VERSION 5.8 ;
BUSBITCHARS "[]" ;
DIVIDERCHAR "/" ;

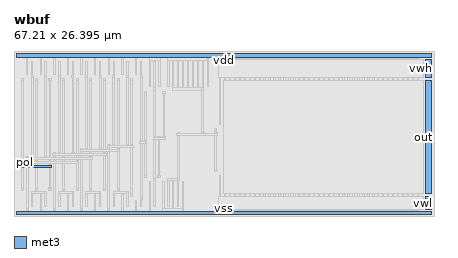
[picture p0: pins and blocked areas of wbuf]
MACRO wbuf
  CLASS BLOCK ;
  FOREIGN wbuf 0 0 ;
  ORIGIN 0 0 ;
  SIZE 67.210 BY 26.395 ;
  SYMMETRY X Y ;
  PIN out
    DIRECTION OUTPUT ;
    USE SIGNAL ;
    PORT
      LAYER met3 ;
        RECT 65.810 3.535 66.750 21.685 ;
    END
  END out
  PIN pol
    DIRECTION INPUT ;
    USE SIGNAL ;
    PORT
      LAYER met3 ;
        RECT 0.460 8.455 1.400 8.795 ;
    END
  END pol
  PIN vdd
    DIRECTION INOUT ;
    USE POWER ;
    PORT
      LAYER met3 ;
        RECT 0.460 25.435 66.750 25.935 ;
    END
  END vdd
  PIN vss
    DIRECTION INOUT ;
    USE GROUND ;
    PORT
      LAYER met3 ;
        RECT 0.460 0.185 66.750 0.685 ;
    END
  END vss
  PIN vwh
    DIRECTION INOUT ;
    USE SIGNAL ;
    PORT
      LAYER met3 ;
        RECT 65.810 22.135 66.750 24.985 ;
    END
  END vwh
  PIN vwl
    DIRECTION INOUT ;
    USE SIGNAL ;
    PORT
      LAYER met3 ;
        RECT 65.810 0.985 66.750 3.085 ;
    END
  END vwl
  PIN wp
    DIRECTION INPUT ;
    USE SIGNAL ;
    PORT
      LAYER met3 ;
        RECT 0.460 7.815 6.020 8.155 ;
    END
  END wp
  OBS
    LAYER li1 ;
      RECT 0.000 0.000 67.210 26.395 ;
    LAYER met1 ;
      RECT 20.220 2.960 20.450 2.965 ;
      RECT 20.170 2.630 20.500 2.960 ;
      RECT 20.220 1.455 20.450 2.630 ;
      RECT 1.940 0.930 1.990 1.260 ;
      RECT 2.220 0.930 2.270 1.260 ;
      RECT 1.990 0.925 2.220 3.455 ;
      RECT 6.300 0.930 6.350 1.260 ;
      RECT 6.580 0.930 6.630 1.260 ;
      RECT 6.350 0.925 6.580 3.455 ;
      RECT 10.660 0.930 10.710 1.260 ;
      RECT 10.940 0.930 10.990 1.260 ;
      RECT 10.710 0.925 10.940 3.455 ;
      RECT 15.020 0.930 15.070 1.260 ;
      RECT 15.300 0.930 15.350 1.260 ;
      RECT 15.070 0.925 15.300 3.455 ;
      RECT 18.680 3.145 19.020 3.485 ;
      RECT 2.780 1.455 3.010 3.625 ;
      RECT 2.780 3.625 4.960 3.965 ;
      RECT 4.960 1.455 5.190 3.965 ;
      RECT 7.140 1.455 7.370 3.625 ;
      RECT 7.140 3.625 9.320 3.965 ;
      RECT 9.320 1.455 9.550 3.965 ;
      RECT 11.500 1.455 11.730 3.625 ;
      RECT 11.500 3.625 13.680 3.965 ;
      RECT 13.680 1.455 13.910 3.965 ;
      RECT 15.860 1.455 16.090 3.625 ;
      RECT 15.860 3.625 18.040 3.965 ;
      RECT 18.040 1.455 18.270 3.965 ;
      RECT 1.240 4.145 1.580 4.485 ;
      RECT 3.420 4.145 3.760 4.485 ;
      RECT 5.600 4.145 5.940 4.485 ;
      RECT 7.780 4.145 8.120 4.485 ;
      RECT 9.960 4.145 10.300 4.485 ;
      RECT 12.140 4.145 12.480 4.485 ;
      RECT 14.320 4.145 14.660 4.485 ;
      RECT 16.500 4.145 16.840 4.485 ;
      RECT 19.430 0.685 19.660 2.455 ;
      RECT 4.170 0.685 4.400 3.455 ;
      RECT 8.530 0.685 8.760 3.455 ;
      RECT 12.890 0.685 13.120 3.455 ;
      RECT 17.250 0.685 17.480 3.455 ;
      RECT 21.610 0.685 21.840 5.455 ;
      RECT 23.790 1.265 24.020 5.455 ;
      RECT 25.370 1.265 25.600 5.455 ;
      RECT 27.180 0.185 66.750 0.685 ;
      RECT 26.950 0.185 27.180 5.455 ;
      RECT 23.790 0.185 26.950 1.265 ;
      RECT 0.460 0.185 23.790 0.685 ;
      RECT 22.400 5.960 22.630 5.965 ;
      RECT 22.350 5.630 22.680 5.960 ;
      RECT 22.400 1.455 22.630 5.630 ;
      RECT 24.580 1.455 24.810 5.625 ;
      RECT 26.390 5.630 26.440 5.960 ;
      RECT 24.580 5.625 26.390 5.965 ;
      RECT 26.160 1.455 26.390 5.625 ;
      RECT 32.890 2.750 33.120 6.455 ;
      RECT 32.840 2.420 33.170 2.750 ;
      RECT 32.890 1.950 33.120 2.420 ;
      RECT 32.840 1.620 33.170 1.950 ;
      RECT 32.890 1.265 33.120 1.620 ;
      RECT 34.470 2.750 34.700 6.455 ;
      RECT 34.420 2.420 34.750 2.750 ;
      RECT 34.470 1.950 34.700 2.420 ;
      RECT 34.420 1.620 34.750 1.950 ;
      RECT 34.470 1.265 34.700 1.620 ;
      RECT 36.050 2.750 36.280 6.455 ;
      RECT 36.000 2.420 36.330 2.750 ;
      RECT 36.050 1.950 36.280 2.420 ;
      RECT 36.000 1.620 36.330 1.950 ;
      RECT 36.050 1.265 36.280 1.620 ;
      RECT 37.630 2.750 37.860 6.455 ;
      RECT 37.580 2.420 37.910 2.750 ;
      RECT 37.630 1.950 37.860 2.420 ;
      RECT 37.580 1.620 37.910 1.950 ;
      RECT 37.630 1.265 37.860 1.620 ;
      RECT 39.210 2.750 39.440 6.455 ;
      RECT 39.160 2.420 39.490 2.750 ;
      RECT 39.210 1.950 39.440 2.420 ;
      RECT 39.160 1.620 39.490 1.950 ;
      RECT 39.210 1.265 39.440 1.620 ;
      RECT 40.790 2.750 41.020 6.455 ;
      RECT 40.740 2.420 41.070 2.750 ;
      RECT 40.790 1.950 41.020 2.420 ;
      RECT 40.740 1.620 41.070 1.950 ;
      RECT 40.790 1.265 41.020 1.620 ;
      RECT 42.370 2.750 42.600 6.455 ;
      RECT 42.320 2.420 42.650 2.750 ;
      RECT 42.370 1.950 42.600 2.420 ;
      RECT 42.320 1.620 42.650 1.950 ;
      RECT 42.370 1.265 42.600 1.620 ;
      RECT 43.950 2.750 44.180 6.455 ;
      RECT 43.900 2.420 44.230 2.750 ;
      RECT 43.950 1.950 44.180 2.420 ;
      RECT 43.900 1.620 44.230 1.950 ;
      RECT 43.950 1.265 44.180 1.620 ;
      RECT 45.530 2.750 45.760 6.455 ;
      RECT 45.480 2.420 45.810 2.750 ;
      RECT 45.530 1.950 45.760 2.420 ;
      RECT 45.480 1.620 45.810 1.950 ;
      RECT 45.530 1.265 45.760 1.620 ;
      RECT 47.110 2.750 47.340 6.455 ;
      RECT 47.060 2.420 47.390 2.750 ;
      RECT 47.110 1.950 47.340 2.420 ;
      RECT 47.060 1.620 47.390 1.950 ;
      RECT 47.110 1.265 47.340 1.620 ;
      RECT 48.690 2.750 48.920 6.455 ;
      RECT 48.640 2.420 48.970 2.750 ;
      RECT 48.690 1.950 48.920 2.420 ;
      RECT 48.640 1.620 48.970 1.950 ;
      RECT 48.690 1.265 48.920 1.620 ;
      RECT 50.270 2.750 50.500 6.455 ;
      RECT 50.220 2.420 50.550 2.750 ;
      RECT 50.270 1.950 50.500 2.420 ;
      RECT 50.220 1.620 50.550 1.950 ;
      RECT 50.270 1.265 50.500 1.620 ;
      RECT 51.850 2.750 52.080 6.455 ;
      RECT 51.800 2.420 52.130 2.750 ;
      RECT 51.850 1.950 52.080 2.420 ;
      RECT 51.800 1.620 52.130 1.950 ;
      RECT 51.850 1.265 52.080 1.620 ;
      RECT 53.430 2.750 53.660 6.455 ;
      RECT 53.380 2.420 53.710 2.750 ;
      RECT 53.430 1.950 53.660 2.420 ;
      RECT 53.380 1.620 53.710 1.950 ;
      RECT 53.430 1.265 53.660 1.620 ;
      RECT 55.010 2.750 55.240 6.455 ;
      RECT 54.960 2.420 55.290 2.750 ;
      RECT 55.010 1.950 55.240 2.420 ;
      RECT 54.960 1.620 55.290 1.950 ;
      RECT 55.010 1.265 55.240 1.620 ;
      RECT 56.590 2.750 56.820 6.455 ;
      RECT 56.540 2.420 56.870 2.750 ;
      RECT 56.590 1.950 56.820 2.420 ;
      RECT 56.540 1.620 56.870 1.950 ;
      RECT 56.590 1.265 56.820 1.620 ;
      RECT 58.170 2.750 58.400 6.455 ;
      RECT 58.120 2.420 58.450 2.750 ;
      RECT 58.170 1.950 58.400 2.420 ;
      RECT 58.120 1.620 58.450 1.950 ;
      RECT 58.170 1.265 58.400 1.620 ;
      RECT 59.750 2.750 59.980 6.455 ;
      RECT 59.700 2.420 60.030 2.750 ;
      RECT 59.750 1.950 59.980 2.420 ;
      RECT 59.700 1.620 60.030 1.950 ;
      RECT 59.750 1.265 59.980 1.620 ;
      RECT 61.330 2.750 61.560 6.455 ;
      RECT 61.280 2.420 61.610 2.750 ;
      RECT 61.330 1.950 61.560 2.420 ;
      RECT 61.280 1.620 61.610 1.950 ;
      RECT 61.330 1.265 61.560 1.620 ;
      RECT 62.910 2.750 63.140 6.455 ;
      RECT 62.860 2.420 63.190 2.750 ;
      RECT 62.910 1.950 63.140 2.420 ;
      RECT 62.860 1.620 63.190 1.950 ;
      RECT 62.910 1.265 63.140 1.620 ;
      RECT 64.490 2.750 64.720 6.455 ;
      RECT 64.440 2.420 64.770 2.750 ;
      RECT 64.490 1.950 64.720 2.420 ;
      RECT 64.440 1.620 64.770 1.950 ;
      RECT 64.490 0.925 64.720 1.620 ;
      RECT 32.890 0.925 64.490 1.265 ;
      RECT 20.860 6.145 21.200 6.485 ;
      RECT 23.040 6.145 23.380 6.485 ;
      RECT 33.680 5.950 33.910 6.625 ;
      RECT 33.630 5.620 33.960 5.950 ;
      RECT 33.680 5.150 33.910 5.620 ;
      RECT 33.630 4.820 33.960 5.150 ;
      RECT 33.680 4.350 33.910 4.820 ;
      RECT 33.630 4.020 33.960 4.350 ;
      RECT 33.680 1.455 33.910 4.020 ;
      RECT 35.260 5.950 35.490 6.625 ;
      RECT 35.210 5.620 35.540 5.950 ;
      RECT 35.260 5.150 35.490 5.620 ;
      RECT 35.210 4.820 35.540 5.150 ;
      RECT 35.260 4.350 35.490 4.820 ;
      RECT 35.210 4.020 35.540 4.350 ;
      RECT 35.260 1.455 35.490 4.020 ;
      RECT 36.840 5.950 37.070 6.625 ;
      RECT 36.790 5.620 37.120 5.950 ;
      RECT 36.840 5.150 37.070 5.620 ;
      RECT 36.790 4.820 37.120 5.150 ;
      RECT 36.840 4.350 37.070 4.820 ;
      RECT 36.790 4.020 37.120 4.350 ;
      RECT 36.840 1.455 37.070 4.020 ;
      RECT 38.420 5.950 38.650 6.625 ;
      RECT 38.370 5.620 38.700 5.950 ;
      RECT 38.420 5.150 38.650 5.620 ;
      RECT 38.370 4.820 38.700 5.150 ;
      RECT 38.420 4.350 38.650 4.820 ;
      RECT 38.370 4.020 38.700 4.350 ;
      RECT 38.420 1.455 38.650 4.020 ;
      RECT 40.000 5.950 40.230 6.625 ;
      RECT 39.950 5.620 40.280 5.950 ;
      RECT 40.000 5.150 40.230 5.620 ;
      RECT 39.950 4.820 40.280 5.150 ;
      RECT 40.000 4.350 40.230 4.820 ;
      RECT 39.950 4.020 40.280 4.350 ;
      RECT 40.000 1.455 40.230 4.020 ;
      RECT 41.580 5.950 41.810 6.625 ;
      RECT 41.530 5.620 41.860 5.950 ;
      RECT 41.580 5.150 41.810 5.620 ;
      RECT 41.530 4.820 41.860 5.150 ;
      RECT 41.580 4.350 41.810 4.820 ;
      RECT 41.530 4.020 41.860 4.350 ;
      RECT 41.580 1.455 41.810 4.020 ;
      RECT 43.160 5.950 43.390 6.625 ;
      RECT 43.110 5.620 43.440 5.950 ;
      RECT 43.160 5.150 43.390 5.620 ;
      RECT 43.110 4.820 43.440 5.150 ;
      RECT 43.160 4.350 43.390 4.820 ;
      RECT 43.110 4.020 43.440 4.350 ;
      RECT 43.160 1.455 43.390 4.020 ;
      RECT 44.740 5.950 44.970 6.625 ;
      RECT 44.690 5.620 45.020 5.950 ;
      RECT 44.740 5.150 44.970 5.620 ;
      RECT 44.690 4.820 45.020 5.150 ;
      RECT 44.740 4.350 44.970 4.820 ;
      RECT 44.690 4.020 45.020 4.350 ;
      RECT 44.740 1.455 44.970 4.020 ;
      RECT 46.320 5.950 46.550 6.625 ;
      RECT 46.270 5.620 46.600 5.950 ;
      RECT 46.320 5.150 46.550 5.620 ;
      RECT 46.270 4.820 46.600 5.150 ;
      RECT 46.320 4.350 46.550 4.820 ;
      RECT 46.270 4.020 46.600 4.350 ;
      RECT 46.320 1.455 46.550 4.020 ;
      RECT 47.900 5.950 48.130 6.625 ;
      RECT 47.850 5.620 48.180 5.950 ;
      RECT 47.900 5.150 48.130 5.620 ;
      RECT 47.850 4.820 48.180 5.150 ;
      RECT 47.900 4.350 48.130 4.820 ;
      RECT 47.850 4.020 48.180 4.350 ;
      RECT 47.900 1.455 48.130 4.020 ;
      RECT 49.480 5.950 49.710 6.625 ;
      RECT 49.430 5.620 49.760 5.950 ;
      RECT 49.480 5.150 49.710 5.620 ;
      RECT 49.430 4.820 49.760 5.150 ;
      RECT 49.480 4.350 49.710 4.820 ;
      RECT 49.430 4.020 49.760 4.350 ;
      RECT 49.480 1.455 49.710 4.020 ;
      RECT 51.060 5.950 51.290 6.625 ;
      RECT 51.010 5.620 51.340 5.950 ;
      RECT 51.060 5.150 51.290 5.620 ;
      RECT 51.010 4.820 51.340 5.150 ;
      RECT 51.060 4.350 51.290 4.820 ;
      RECT 51.010 4.020 51.340 4.350 ;
      RECT 51.060 1.455 51.290 4.020 ;
      RECT 52.640 5.950 52.870 6.625 ;
      RECT 52.590 5.620 52.920 5.950 ;
      RECT 52.640 5.150 52.870 5.620 ;
      RECT 52.590 4.820 52.920 5.150 ;
      RECT 52.640 4.350 52.870 4.820 ;
      RECT 52.590 4.020 52.920 4.350 ;
      RECT 52.640 1.455 52.870 4.020 ;
      RECT 54.220 5.950 54.450 6.625 ;
      RECT 54.170 5.620 54.500 5.950 ;
      RECT 54.220 5.150 54.450 5.620 ;
      RECT 54.170 4.820 54.500 5.150 ;
      RECT 54.220 4.350 54.450 4.820 ;
      RECT 54.170 4.020 54.500 4.350 ;
      RECT 54.220 1.455 54.450 4.020 ;
      RECT 55.800 5.950 56.030 6.625 ;
      RECT 55.750 5.620 56.080 5.950 ;
      RECT 55.800 5.150 56.030 5.620 ;
      RECT 55.750 4.820 56.080 5.150 ;
      RECT 55.800 4.350 56.030 4.820 ;
      RECT 55.750 4.020 56.080 4.350 ;
      RECT 55.800 1.455 56.030 4.020 ;
      RECT 57.380 5.950 57.610 6.625 ;
      RECT 57.330 5.620 57.660 5.950 ;
      RECT 57.380 5.150 57.610 5.620 ;
      RECT 57.330 4.820 57.660 5.150 ;
      RECT 57.380 4.350 57.610 4.820 ;
      RECT 57.330 4.020 57.660 4.350 ;
      RECT 57.380 1.455 57.610 4.020 ;
      RECT 58.960 5.950 59.190 6.625 ;
      RECT 58.910 5.620 59.240 5.950 ;
      RECT 58.960 5.150 59.190 5.620 ;
      RECT 58.910 4.820 59.240 5.150 ;
      RECT 58.960 4.350 59.190 4.820 ;
      RECT 58.910 4.020 59.240 4.350 ;
      RECT 58.960 1.455 59.190 4.020 ;
      RECT 60.540 5.950 60.770 6.625 ;
      RECT 60.490 5.620 60.820 5.950 ;
      RECT 60.540 5.150 60.770 5.620 ;
      RECT 60.490 4.820 60.820 5.150 ;
      RECT 60.540 4.350 60.770 4.820 ;
      RECT 60.490 4.020 60.820 4.350 ;
      RECT 60.540 1.455 60.770 4.020 ;
      RECT 62.120 5.950 62.350 6.625 ;
      RECT 62.070 5.620 62.400 5.950 ;
      RECT 62.120 5.150 62.350 5.620 ;
      RECT 62.070 4.820 62.400 5.150 ;
      RECT 62.120 4.350 62.350 4.820 ;
      RECT 62.070 4.020 62.400 4.350 ;
      RECT 62.120 1.455 62.350 4.020 ;
      RECT 33.680 6.625 63.700 6.965 ;
      RECT 63.700 5.950 63.930 6.965 ;
      RECT 63.650 5.620 63.980 5.950 ;
      RECT 63.700 5.150 63.930 5.620 ;
      RECT 63.650 4.820 63.980 5.150 ;
      RECT 63.700 4.350 63.930 4.820 ;
      RECT 63.650 4.020 63.980 4.350 ;
      RECT 63.700 1.455 63.930 4.020 ;
      RECT 32.140 7.145 32.480 7.485 ;
      RECT 32.140 13.635 32.480 13.975 ;
      RECT 20.860 19.635 21.200 19.975 ;
      RECT 23.830 19.635 24.170 19.975 ;
      RECT 1.240 21.635 1.580 21.975 ;
      RECT 3.420 21.635 3.760 21.975 ;
      RECT 5.600 21.635 5.940 21.975 ;
      RECT 7.780 21.635 8.120 21.975 ;
      RECT 9.960 21.635 10.300 21.975 ;
      RECT 12.140 21.635 12.480 21.975 ;
      RECT 14.320 21.635 14.660 21.975 ;
      RECT 16.500 21.635 16.840 21.975 ;
      RECT 18.680 21.635 19.020 21.975 ;
      RECT 2.730 22.160 2.780 22.490 ;
      RECT 3.010 22.160 3.060 22.490 ;
      RECT 2.780 22.155 3.010 24.665 ;
      RECT 4.910 22.160 4.960 22.490 ;
      RECT 5.190 22.160 5.240 22.490 ;
      RECT 4.960 22.155 5.190 24.665 ;
      RECT 7.090 22.160 7.140 22.490 ;
      RECT 7.370 22.160 7.420 22.490 ;
      RECT 7.140 22.155 7.370 24.665 ;
      RECT 9.270 22.160 9.320 22.490 ;
      RECT 9.550 22.160 9.600 22.490 ;
      RECT 9.320 22.155 9.550 24.665 ;
      RECT 11.450 22.160 11.500 22.490 ;
      RECT 11.730 22.160 11.780 22.490 ;
      RECT 11.500 22.155 11.730 24.665 ;
      RECT 13.630 22.160 13.680 22.490 ;
      RECT 13.910 22.160 13.960 22.490 ;
      RECT 13.680 22.155 13.910 24.665 ;
      RECT 15.810 22.160 15.860 22.490 ;
      RECT 16.090 22.160 16.140 22.490 ;
      RECT 15.860 22.155 16.090 24.665 ;
      RECT 17.990 22.160 18.040 22.490 ;
      RECT 18.270 22.160 18.320 22.490 ;
      RECT 18.040 22.155 18.270 24.665 ;
      RECT 20.170 22.160 20.220 22.490 ;
      RECT 20.450 22.160 20.500 22.490 ;
      RECT 20.220 22.155 20.450 24.665 ;
      RECT 22.350 20.160 22.400 20.490 ;
      RECT 22.630 20.160 22.680 20.490 ;
      RECT 22.400 20.155 22.630 24.665 ;
      RECT 25.370 20.495 25.600 24.665 ;
      RECT 26.950 20.495 27.180 24.665 ;
      RECT 28.530 20.495 28.760 24.665 ;
      RECT 30.340 20.160 30.390 20.490 ;
      RECT 30.110 20.155 30.340 24.665 ;
      RECT 25.370 20.155 30.110 20.495 ;
      RECT 33.680 20.950 33.910 24.665 ;
      RECT 33.630 20.620 33.960 20.950 ;
      RECT 33.680 20.150 33.910 20.620 ;
      RECT 33.630 19.820 33.960 20.150 ;
      RECT 33.680 19.350 33.910 19.820 ;
      RECT 33.630 19.020 33.960 19.350 ;
      RECT 33.680 18.550 33.910 19.020 ;
      RECT 33.630 18.220 33.960 18.550 ;
      RECT 33.680 17.750 33.910 18.220 ;
      RECT 33.630 17.420 33.960 17.750 ;
      RECT 33.680 16.950 33.910 17.420 ;
      RECT 33.630 16.620 33.960 16.950 ;
      RECT 33.680 16.150 33.910 16.620 ;
      RECT 33.630 15.820 33.960 16.150 ;
      RECT 33.680 15.350 33.910 15.820 ;
      RECT 33.630 15.020 33.960 15.350 ;
      RECT 33.680 14.495 33.910 15.020 ;
      RECT 35.260 20.950 35.490 24.665 ;
      RECT 35.210 20.620 35.540 20.950 ;
      RECT 35.260 20.150 35.490 20.620 ;
      RECT 35.210 19.820 35.540 20.150 ;
      RECT 35.260 19.350 35.490 19.820 ;
      RECT 35.210 19.020 35.540 19.350 ;
      RECT 35.260 18.550 35.490 19.020 ;
      RECT 35.210 18.220 35.540 18.550 ;
      RECT 35.260 17.750 35.490 18.220 ;
      RECT 35.210 17.420 35.540 17.750 ;
      RECT 35.260 16.950 35.490 17.420 ;
      RECT 35.210 16.620 35.540 16.950 ;
      RECT 35.260 16.150 35.490 16.620 ;
      RECT 35.210 15.820 35.540 16.150 ;
      RECT 35.260 15.350 35.490 15.820 ;
      RECT 35.210 15.020 35.540 15.350 ;
      RECT 35.260 14.495 35.490 15.020 ;
      RECT 36.840 20.950 37.070 24.665 ;
      RECT 36.790 20.620 37.120 20.950 ;
      RECT 36.840 20.150 37.070 20.620 ;
      RECT 36.790 19.820 37.120 20.150 ;
      RECT 36.840 19.350 37.070 19.820 ;
      RECT 36.790 19.020 37.120 19.350 ;
      RECT 36.840 18.550 37.070 19.020 ;
      RECT 36.790 18.220 37.120 18.550 ;
      RECT 36.840 17.750 37.070 18.220 ;
      RECT 36.790 17.420 37.120 17.750 ;
      RECT 36.840 16.950 37.070 17.420 ;
      RECT 36.790 16.620 37.120 16.950 ;
      RECT 36.840 16.150 37.070 16.620 ;
      RECT 36.790 15.820 37.120 16.150 ;
      RECT 36.840 15.350 37.070 15.820 ;
      RECT 36.790 15.020 37.120 15.350 ;
      RECT 36.840 14.495 37.070 15.020 ;
      RECT 38.420 20.950 38.650 24.665 ;
      RECT 38.370 20.620 38.700 20.950 ;
      RECT 38.420 20.150 38.650 20.620 ;
      RECT 38.370 19.820 38.700 20.150 ;
      RECT 38.420 19.350 38.650 19.820 ;
      RECT 38.370 19.020 38.700 19.350 ;
      RECT 38.420 18.550 38.650 19.020 ;
      RECT 38.370 18.220 38.700 18.550 ;
      RECT 38.420 17.750 38.650 18.220 ;
      RECT 38.370 17.420 38.700 17.750 ;
      RECT 38.420 16.950 38.650 17.420 ;
      RECT 38.370 16.620 38.700 16.950 ;
      RECT 38.420 16.150 38.650 16.620 ;
      RECT 38.370 15.820 38.700 16.150 ;
      RECT 38.420 15.350 38.650 15.820 ;
      RECT 38.370 15.020 38.700 15.350 ;
      RECT 38.420 14.495 38.650 15.020 ;
      RECT 40.000 20.950 40.230 24.665 ;
      RECT 39.950 20.620 40.280 20.950 ;
      RECT 40.000 20.150 40.230 20.620 ;
      RECT 39.950 19.820 40.280 20.150 ;
      RECT 40.000 19.350 40.230 19.820 ;
      RECT 39.950 19.020 40.280 19.350 ;
      RECT 40.000 18.550 40.230 19.020 ;
      RECT 39.950 18.220 40.280 18.550 ;
      RECT 40.000 17.750 40.230 18.220 ;
      RECT 39.950 17.420 40.280 17.750 ;
      RECT 40.000 16.950 40.230 17.420 ;
      RECT 39.950 16.620 40.280 16.950 ;
      RECT 40.000 16.150 40.230 16.620 ;
      RECT 39.950 15.820 40.280 16.150 ;
      RECT 40.000 15.350 40.230 15.820 ;
      RECT 39.950 15.020 40.280 15.350 ;
      RECT 40.000 14.495 40.230 15.020 ;
      RECT 41.580 20.950 41.810 24.665 ;
      RECT 41.530 20.620 41.860 20.950 ;
      RECT 41.580 20.150 41.810 20.620 ;
      RECT 41.530 19.820 41.860 20.150 ;
      RECT 41.580 19.350 41.810 19.820 ;
      RECT 41.530 19.020 41.860 19.350 ;
      RECT 41.580 18.550 41.810 19.020 ;
      RECT 41.530 18.220 41.860 18.550 ;
      RECT 41.580 17.750 41.810 18.220 ;
      RECT 41.530 17.420 41.860 17.750 ;
      RECT 41.580 16.950 41.810 17.420 ;
      RECT 41.530 16.620 41.860 16.950 ;
      RECT 41.580 16.150 41.810 16.620 ;
      RECT 41.530 15.820 41.860 16.150 ;
      RECT 41.580 15.350 41.810 15.820 ;
      RECT 41.530 15.020 41.860 15.350 ;
      RECT 41.580 14.495 41.810 15.020 ;
      RECT 43.160 20.950 43.390 24.665 ;
      RECT 43.110 20.620 43.440 20.950 ;
      RECT 43.160 20.150 43.390 20.620 ;
      RECT 43.110 19.820 43.440 20.150 ;
      RECT 43.160 19.350 43.390 19.820 ;
      RECT 43.110 19.020 43.440 19.350 ;
      RECT 43.160 18.550 43.390 19.020 ;
      RECT 43.110 18.220 43.440 18.550 ;
      RECT 43.160 17.750 43.390 18.220 ;
      RECT 43.110 17.420 43.440 17.750 ;
      RECT 43.160 16.950 43.390 17.420 ;
      RECT 43.110 16.620 43.440 16.950 ;
      RECT 43.160 16.150 43.390 16.620 ;
      RECT 43.110 15.820 43.440 16.150 ;
      RECT 43.160 15.350 43.390 15.820 ;
      RECT 43.110 15.020 43.440 15.350 ;
      RECT 43.160 14.495 43.390 15.020 ;
      RECT 44.740 20.950 44.970 24.665 ;
      RECT 44.690 20.620 45.020 20.950 ;
      RECT 44.740 20.150 44.970 20.620 ;
      RECT 44.690 19.820 45.020 20.150 ;
      RECT 44.740 19.350 44.970 19.820 ;
      RECT 44.690 19.020 45.020 19.350 ;
      RECT 44.740 18.550 44.970 19.020 ;
      RECT 44.690 18.220 45.020 18.550 ;
      RECT 44.740 17.750 44.970 18.220 ;
      RECT 44.690 17.420 45.020 17.750 ;
      RECT 44.740 16.950 44.970 17.420 ;
      RECT 44.690 16.620 45.020 16.950 ;
      RECT 44.740 16.150 44.970 16.620 ;
      RECT 44.690 15.820 45.020 16.150 ;
      RECT 44.740 15.350 44.970 15.820 ;
      RECT 44.690 15.020 45.020 15.350 ;
      RECT 44.740 14.495 44.970 15.020 ;
      RECT 46.320 20.950 46.550 24.665 ;
      RECT 46.270 20.620 46.600 20.950 ;
      RECT 46.320 20.150 46.550 20.620 ;
      RECT 46.270 19.820 46.600 20.150 ;
      RECT 46.320 19.350 46.550 19.820 ;
      RECT 46.270 19.020 46.600 19.350 ;
      RECT 46.320 18.550 46.550 19.020 ;
      RECT 46.270 18.220 46.600 18.550 ;
      RECT 46.320 17.750 46.550 18.220 ;
      RECT 46.270 17.420 46.600 17.750 ;
      RECT 46.320 16.950 46.550 17.420 ;
      RECT 46.270 16.620 46.600 16.950 ;
      RECT 46.320 16.150 46.550 16.620 ;
      RECT 46.270 15.820 46.600 16.150 ;
      RECT 46.320 15.350 46.550 15.820 ;
      RECT 46.270 15.020 46.600 15.350 ;
      RECT 46.320 14.495 46.550 15.020 ;
      RECT 47.900 20.950 48.130 24.665 ;
      RECT 47.850 20.620 48.180 20.950 ;
      RECT 47.900 20.150 48.130 20.620 ;
      RECT 47.850 19.820 48.180 20.150 ;
      RECT 47.900 19.350 48.130 19.820 ;
      RECT 47.850 19.020 48.180 19.350 ;
      RECT 47.900 18.550 48.130 19.020 ;
      RECT 47.850 18.220 48.180 18.550 ;
      RECT 47.900 17.750 48.130 18.220 ;
      RECT 47.850 17.420 48.180 17.750 ;
      RECT 47.900 16.950 48.130 17.420 ;
      RECT 47.850 16.620 48.180 16.950 ;
      RECT 47.900 16.150 48.130 16.620 ;
      RECT 47.850 15.820 48.180 16.150 ;
      RECT 47.900 15.350 48.130 15.820 ;
      RECT 47.850 15.020 48.180 15.350 ;
      RECT 47.900 14.495 48.130 15.020 ;
      RECT 49.480 20.950 49.710 24.665 ;
      RECT 49.430 20.620 49.760 20.950 ;
      RECT 49.480 20.150 49.710 20.620 ;
      RECT 49.430 19.820 49.760 20.150 ;
      RECT 49.480 19.350 49.710 19.820 ;
      RECT 49.430 19.020 49.760 19.350 ;
      RECT 49.480 18.550 49.710 19.020 ;
      RECT 49.430 18.220 49.760 18.550 ;
      RECT 49.480 17.750 49.710 18.220 ;
      RECT 49.430 17.420 49.760 17.750 ;
      RECT 49.480 16.950 49.710 17.420 ;
      RECT 49.430 16.620 49.760 16.950 ;
      RECT 49.480 16.150 49.710 16.620 ;
      RECT 49.430 15.820 49.760 16.150 ;
      RECT 49.480 15.350 49.710 15.820 ;
      RECT 49.430 15.020 49.760 15.350 ;
      RECT 49.480 14.495 49.710 15.020 ;
      RECT 51.060 20.950 51.290 24.665 ;
      RECT 51.010 20.620 51.340 20.950 ;
      RECT 51.060 20.150 51.290 20.620 ;
      RECT 51.010 19.820 51.340 20.150 ;
      RECT 51.060 19.350 51.290 19.820 ;
      RECT 51.010 19.020 51.340 19.350 ;
      RECT 51.060 18.550 51.290 19.020 ;
      RECT 51.010 18.220 51.340 18.550 ;
      RECT 51.060 17.750 51.290 18.220 ;
      RECT 51.010 17.420 51.340 17.750 ;
      RECT 51.060 16.950 51.290 17.420 ;
      RECT 51.010 16.620 51.340 16.950 ;
      RECT 51.060 16.150 51.290 16.620 ;
      RECT 51.010 15.820 51.340 16.150 ;
      RECT 51.060 15.350 51.290 15.820 ;
      RECT 51.010 15.020 51.340 15.350 ;
      RECT 51.060 14.495 51.290 15.020 ;
      RECT 52.640 20.950 52.870 24.665 ;
      RECT 52.590 20.620 52.920 20.950 ;
      RECT 52.640 20.150 52.870 20.620 ;
      RECT 52.590 19.820 52.920 20.150 ;
      RECT 52.640 19.350 52.870 19.820 ;
      RECT 52.590 19.020 52.920 19.350 ;
      RECT 52.640 18.550 52.870 19.020 ;
      RECT 52.590 18.220 52.920 18.550 ;
      RECT 52.640 17.750 52.870 18.220 ;
      RECT 52.590 17.420 52.920 17.750 ;
      RECT 52.640 16.950 52.870 17.420 ;
      RECT 52.590 16.620 52.920 16.950 ;
      RECT 52.640 16.150 52.870 16.620 ;
      RECT 52.590 15.820 52.920 16.150 ;
      RECT 52.640 15.350 52.870 15.820 ;
      RECT 52.590 15.020 52.920 15.350 ;
      RECT 52.640 14.495 52.870 15.020 ;
      RECT 54.220 20.950 54.450 24.665 ;
      RECT 54.170 20.620 54.500 20.950 ;
      RECT 54.220 20.150 54.450 20.620 ;
      RECT 54.170 19.820 54.500 20.150 ;
      RECT 54.220 19.350 54.450 19.820 ;
      RECT 54.170 19.020 54.500 19.350 ;
      RECT 54.220 18.550 54.450 19.020 ;
      RECT 54.170 18.220 54.500 18.550 ;
      RECT 54.220 17.750 54.450 18.220 ;
      RECT 54.170 17.420 54.500 17.750 ;
      RECT 54.220 16.950 54.450 17.420 ;
      RECT 54.170 16.620 54.500 16.950 ;
      RECT 54.220 16.150 54.450 16.620 ;
      RECT 54.170 15.820 54.500 16.150 ;
      RECT 54.220 15.350 54.450 15.820 ;
      RECT 54.170 15.020 54.500 15.350 ;
      RECT 54.220 14.495 54.450 15.020 ;
      RECT 55.800 20.950 56.030 24.665 ;
      RECT 55.750 20.620 56.080 20.950 ;
      RECT 55.800 20.150 56.030 20.620 ;
      RECT 55.750 19.820 56.080 20.150 ;
      RECT 55.800 19.350 56.030 19.820 ;
      RECT 55.750 19.020 56.080 19.350 ;
      RECT 55.800 18.550 56.030 19.020 ;
      RECT 55.750 18.220 56.080 18.550 ;
      RECT 55.800 17.750 56.030 18.220 ;
      RECT 55.750 17.420 56.080 17.750 ;
      RECT 55.800 16.950 56.030 17.420 ;
      RECT 55.750 16.620 56.080 16.950 ;
      RECT 55.800 16.150 56.030 16.620 ;
      RECT 55.750 15.820 56.080 16.150 ;
      RECT 55.800 15.350 56.030 15.820 ;
      RECT 55.750 15.020 56.080 15.350 ;
      RECT 55.800 14.495 56.030 15.020 ;
      RECT 57.380 20.950 57.610 24.665 ;
      RECT 57.330 20.620 57.660 20.950 ;
      RECT 57.380 20.150 57.610 20.620 ;
      RECT 57.330 19.820 57.660 20.150 ;
      RECT 57.380 19.350 57.610 19.820 ;
      RECT 57.330 19.020 57.660 19.350 ;
      RECT 57.380 18.550 57.610 19.020 ;
      RECT 57.330 18.220 57.660 18.550 ;
      RECT 57.380 17.750 57.610 18.220 ;
      RECT 57.330 17.420 57.660 17.750 ;
      RECT 57.380 16.950 57.610 17.420 ;
      RECT 57.330 16.620 57.660 16.950 ;
      RECT 57.380 16.150 57.610 16.620 ;
      RECT 57.330 15.820 57.660 16.150 ;
      RECT 57.380 15.350 57.610 15.820 ;
      RECT 57.330 15.020 57.660 15.350 ;
      RECT 57.380 14.495 57.610 15.020 ;
      RECT 58.960 20.950 59.190 24.665 ;
      RECT 58.910 20.620 59.240 20.950 ;
      RECT 58.960 20.150 59.190 20.620 ;
      RECT 58.910 19.820 59.240 20.150 ;
      RECT 58.960 19.350 59.190 19.820 ;
      RECT 58.910 19.020 59.240 19.350 ;
      RECT 58.960 18.550 59.190 19.020 ;
      RECT 58.910 18.220 59.240 18.550 ;
      RECT 58.960 17.750 59.190 18.220 ;
      RECT 58.910 17.420 59.240 17.750 ;
      RECT 58.960 16.950 59.190 17.420 ;
      RECT 58.910 16.620 59.240 16.950 ;
      RECT 58.960 16.150 59.190 16.620 ;
      RECT 58.910 15.820 59.240 16.150 ;
      RECT 58.960 15.350 59.190 15.820 ;
      RECT 58.910 15.020 59.240 15.350 ;
      RECT 58.960 14.495 59.190 15.020 ;
      RECT 60.540 20.950 60.770 24.665 ;
      RECT 60.490 20.620 60.820 20.950 ;
      RECT 60.540 20.150 60.770 20.620 ;
      RECT 60.490 19.820 60.820 20.150 ;
      RECT 60.540 19.350 60.770 19.820 ;
      RECT 60.490 19.020 60.820 19.350 ;
      RECT 60.540 18.550 60.770 19.020 ;
      RECT 60.490 18.220 60.820 18.550 ;
      RECT 60.540 17.750 60.770 18.220 ;
      RECT 60.490 17.420 60.820 17.750 ;
      RECT 60.540 16.950 60.770 17.420 ;
      RECT 60.490 16.620 60.820 16.950 ;
      RECT 60.540 16.150 60.770 16.620 ;
      RECT 60.490 15.820 60.820 16.150 ;
      RECT 60.540 15.350 60.770 15.820 ;
      RECT 60.490 15.020 60.820 15.350 ;
      RECT 60.540 14.495 60.770 15.020 ;
      RECT 62.120 20.950 62.350 24.665 ;
      RECT 62.070 20.620 62.400 20.950 ;
      RECT 62.120 20.150 62.350 20.620 ;
      RECT 62.070 19.820 62.400 20.150 ;
      RECT 62.120 19.350 62.350 19.820 ;
      RECT 62.070 19.020 62.400 19.350 ;
      RECT 62.120 18.550 62.350 19.020 ;
      RECT 62.070 18.220 62.400 18.550 ;
      RECT 62.120 17.750 62.350 18.220 ;
      RECT 62.070 17.420 62.400 17.750 ;
      RECT 62.120 16.950 62.350 17.420 ;
      RECT 62.070 16.620 62.400 16.950 ;
      RECT 62.120 16.150 62.350 16.620 ;
      RECT 62.070 15.820 62.400 16.150 ;
      RECT 62.120 15.350 62.350 15.820 ;
      RECT 62.070 15.020 62.400 15.350 ;
      RECT 62.120 14.495 62.350 15.020 ;
      RECT 63.700 20.950 63.930 24.665 ;
      RECT 63.650 20.620 63.980 20.950 ;
      RECT 63.700 20.150 63.930 20.620 ;
      RECT 63.650 19.820 63.980 20.150 ;
      RECT 63.700 19.350 63.930 19.820 ;
      RECT 63.650 19.020 63.980 19.350 ;
      RECT 63.700 18.550 63.930 19.020 ;
      RECT 63.650 18.220 63.980 18.550 ;
      RECT 63.700 17.750 63.930 18.220 ;
      RECT 63.650 17.420 63.980 17.750 ;
      RECT 63.700 16.950 63.930 17.420 ;
      RECT 63.650 16.620 63.980 16.950 ;
      RECT 63.700 16.150 63.930 16.620 ;
      RECT 63.650 15.820 63.980 16.150 ;
      RECT 63.700 15.350 63.930 15.820 ;
      RECT 63.650 15.020 63.980 15.350 ;
      RECT 63.700 14.155 63.930 15.020 ;
      RECT 33.680 14.155 63.700 14.495 ;
      RECT 32.890 24.350 33.120 24.855 ;
      RECT 32.840 24.020 33.170 24.350 ;
      RECT 32.890 23.550 33.120 24.020 ;
      RECT 32.840 23.220 33.170 23.550 ;
      RECT 32.890 22.750 33.120 23.220 ;
      RECT 32.840 22.420 33.170 22.750 ;
      RECT 32.890 14.665 33.120 22.420 ;
      RECT 34.470 24.350 34.700 24.855 ;
      RECT 34.420 24.020 34.750 24.350 ;
      RECT 34.470 23.550 34.700 24.020 ;
      RECT 34.420 23.220 34.750 23.550 ;
      RECT 34.470 22.750 34.700 23.220 ;
      RECT 34.420 22.420 34.750 22.750 ;
      RECT 34.470 14.665 34.700 22.420 ;
      RECT 36.050 24.350 36.280 24.855 ;
      RECT 36.000 24.020 36.330 24.350 ;
      RECT 36.050 23.550 36.280 24.020 ;
      RECT 36.000 23.220 36.330 23.550 ;
      RECT 36.050 22.750 36.280 23.220 ;
      RECT 36.000 22.420 36.330 22.750 ;
      RECT 36.050 14.665 36.280 22.420 ;
      RECT 37.630 24.350 37.860 24.855 ;
      RECT 37.580 24.020 37.910 24.350 ;
      RECT 37.630 23.550 37.860 24.020 ;
      RECT 37.580 23.220 37.910 23.550 ;
      RECT 37.630 22.750 37.860 23.220 ;
      RECT 37.580 22.420 37.910 22.750 ;
      RECT 37.630 14.665 37.860 22.420 ;
      RECT 39.210 24.350 39.440 24.855 ;
      RECT 39.160 24.020 39.490 24.350 ;
      RECT 39.210 23.550 39.440 24.020 ;
      RECT 39.160 23.220 39.490 23.550 ;
      RECT 39.210 22.750 39.440 23.220 ;
      RECT 39.160 22.420 39.490 22.750 ;
      RECT 39.210 14.665 39.440 22.420 ;
      RECT 40.790 24.350 41.020 24.855 ;
      RECT 40.740 24.020 41.070 24.350 ;
      RECT 40.790 23.550 41.020 24.020 ;
      RECT 40.740 23.220 41.070 23.550 ;
      RECT 40.790 22.750 41.020 23.220 ;
      RECT 40.740 22.420 41.070 22.750 ;
      RECT 40.790 14.665 41.020 22.420 ;
      RECT 42.370 24.350 42.600 24.855 ;
      RECT 42.320 24.020 42.650 24.350 ;
      RECT 42.370 23.550 42.600 24.020 ;
      RECT 42.320 23.220 42.650 23.550 ;
      RECT 42.370 22.750 42.600 23.220 ;
      RECT 42.320 22.420 42.650 22.750 ;
      RECT 42.370 14.665 42.600 22.420 ;
      RECT 43.950 24.350 44.180 24.855 ;
      RECT 43.900 24.020 44.230 24.350 ;
      RECT 43.950 23.550 44.180 24.020 ;
      RECT 43.900 23.220 44.230 23.550 ;
      RECT 43.950 22.750 44.180 23.220 ;
      RECT 43.900 22.420 44.230 22.750 ;
      RECT 43.950 14.665 44.180 22.420 ;
      RECT 45.530 24.350 45.760 24.855 ;
      RECT 45.480 24.020 45.810 24.350 ;
      RECT 45.530 23.550 45.760 24.020 ;
      RECT 45.480 23.220 45.810 23.550 ;
      RECT 45.530 22.750 45.760 23.220 ;
      RECT 45.480 22.420 45.810 22.750 ;
      RECT 45.530 14.665 45.760 22.420 ;
      RECT 47.110 24.350 47.340 24.855 ;
      RECT 47.060 24.020 47.390 24.350 ;
      RECT 47.110 23.550 47.340 24.020 ;
      RECT 47.060 23.220 47.390 23.550 ;
      RECT 47.110 22.750 47.340 23.220 ;
      RECT 47.060 22.420 47.390 22.750 ;
      RECT 47.110 14.665 47.340 22.420 ;
      RECT 48.690 24.350 48.920 24.855 ;
      RECT 48.640 24.020 48.970 24.350 ;
      RECT 48.690 23.550 48.920 24.020 ;
      RECT 48.640 23.220 48.970 23.550 ;
      RECT 48.690 22.750 48.920 23.220 ;
      RECT 48.640 22.420 48.970 22.750 ;
      RECT 48.690 14.665 48.920 22.420 ;
      RECT 50.270 24.350 50.500 24.855 ;
      RECT 50.220 24.020 50.550 24.350 ;
      RECT 50.270 23.550 50.500 24.020 ;
      RECT 50.220 23.220 50.550 23.550 ;
      RECT 50.270 22.750 50.500 23.220 ;
      RECT 50.220 22.420 50.550 22.750 ;
      RECT 50.270 14.665 50.500 22.420 ;
      RECT 51.850 24.350 52.080 24.855 ;
      RECT 51.800 24.020 52.130 24.350 ;
      RECT 51.850 23.550 52.080 24.020 ;
      RECT 51.800 23.220 52.130 23.550 ;
      RECT 51.850 22.750 52.080 23.220 ;
      RECT 51.800 22.420 52.130 22.750 ;
      RECT 51.850 14.665 52.080 22.420 ;
      RECT 53.430 24.350 53.660 24.855 ;
      RECT 53.380 24.020 53.710 24.350 ;
      RECT 53.430 23.550 53.660 24.020 ;
      RECT 53.380 23.220 53.710 23.550 ;
      RECT 53.430 22.750 53.660 23.220 ;
      RECT 53.380 22.420 53.710 22.750 ;
      RECT 53.430 14.665 53.660 22.420 ;
      RECT 55.010 24.350 55.240 24.855 ;
      RECT 54.960 24.020 55.290 24.350 ;
      RECT 55.010 23.550 55.240 24.020 ;
      RECT 54.960 23.220 55.290 23.550 ;
      RECT 55.010 22.750 55.240 23.220 ;
      RECT 54.960 22.420 55.290 22.750 ;
      RECT 55.010 14.665 55.240 22.420 ;
      RECT 56.590 24.350 56.820 24.855 ;
      RECT 56.540 24.020 56.870 24.350 ;
      RECT 56.590 23.550 56.820 24.020 ;
      RECT 56.540 23.220 56.870 23.550 ;
      RECT 56.590 22.750 56.820 23.220 ;
      RECT 56.540 22.420 56.870 22.750 ;
      RECT 56.590 14.665 56.820 22.420 ;
      RECT 58.170 24.350 58.400 24.855 ;
      RECT 58.120 24.020 58.450 24.350 ;
      RECT 58.170 23.550 58.400 24.020 ;
      RECT 58.120 23.220 58.450 23.550 ;
      RECT 58.170 22.750 58.400 23.220 ;
      RECT 58.120 22.420 58.450 22.750 ;
      RECT 58.170 14.665 58.400 22.420 ;
      RECT 59.750 24.350 59.980 24.855 ;
      RECT 59.700 24.020 60.030 24.350 ;
      RECT 59.750 23.550 59.980 24.020 ;
      RECT 59.700 23.220 60.030 23.550 ;
      RECT 59.750 22.750 59.980 23.220 ;
      RECT 59.700 22.420 60.030 22.750 ;
      RECT 59.750 14.665 59.980 22.420 ;
      RECT 61.330 24.350 61.560 24.855 ;
      RECT 61.280 24.020 61.610 24.350 ;
      RECT 61.330 23.550 61.560 24.020 ;
      RECT 61.280 23.220 61.610 23.550 ;
      RECT 61.330 22.750 61.560 23.220 ;
      RECT 61.280 22.420 61.610 22.750 ;
      RECT 61.330 14.665 61.560 22.420 ;
      RECT 62.910 24.350 63.140 24.855 ;
      RECT 62.860 24.020 63.190 24.350 ;
      RECT 62.910 23.550 63.140 24.020 ;
      RECT 62.860 23.220 63.190 23.550 ;
      RECT 62.910 22.750 63.140 23.220 ;
      RECT 62.860 22.420 63.190 22.750 ;
      RECT 62.910 14.665 63.140 22.420 ;
      RECT 32.890 24.855 64.490 25.195 ;
      RECT 64.490 24.350 64.720 25.195 ;
      RECT 64.440 24.020 64.770 24.350 ;
      RECT 64.490 23.550 64.720 24.020 ;
      RECT 64.440 23.220 64.770 23.550 ;
      RECT 64.490 22.750 64.720 23.220 ;
      RECT 64.440 22.420 64.770 22.750 ;
      RECT 64.490 14.665 64.720 22.420 ;
      RECT 21.610 20.665 21.840 24.855 ;
      RECT 24.580 20.665 24.810 24.855 ;
      RECT 26.160 20.665 26.390 24.855 ;
      RECT 27.740 20.665 27.970 24.855 ;
      RECT 29.320 20.665 29.550 24.855 ;
      RECT 1.990 22.665 2.220 25.435 ;
      RECT 4.170 22.665 4.400 25.435 ;
      RECT 6.350 22.665 6.580 25.435 ;
      RECT 8.530 22.665 8.760 25.435 ;
      RECT 10.710 22.665 10.940 25.435 ;
      RECT 12.890 22.665 13.120 25.435 ;
      RECT 15.070 22.665 15.300 25.435 ;
      RECT 17.250 22.665 17.480 25.435 ;
      RECT 19.430 22.665 19.660 25.435 ;
      RECT 21.610 24.855 23.420 25.435 ;
      RECT 23.190 20.665 23.420 24.855 ;
      RECT 0.460 25.435 24.580 25.935 ;
      RECT 24.580 24.855 30.900 25.935 ;
      RECT 30.900 20.665 31.130 25.935 ;
      RECT 31.130 25.435 66.750 25.935 ;
    LAYER met2 ;
      RECT 0.460 0.185 66.750 0.685 ;
      RECT 26.090 12.920 26.460 13.290 ;
      RECT 26.125 5.960 26.425 12.920 ;
      RECT 26.110 5.630 26.440 5.960 ;
      RECT 32.145 13.640 32.475 13.970 ;
      RECT 32.160 13.290 32.460 13.640 ;
      RECT 32.125 12.920 32.495 13.290 ;
      RECT 32.160 7.480 32.460 12.920 ;
      RECT 32.145 7.150 32.475 7.480 ;
      RECT 20.865 19.640 21.195 19.970 ;
      RECT 20.880 12.010 21.180 19.640 ;
      RECT 20.845 11.640 21.215 12.010 ;
      RECT 20.880 6.480 21.180 11.640 ;
      RECT 20.865 6.150 21.195 6.480 ;
      RECT 23.835 19.640 24.165 19.970 ;
      RECT 23.850 12.650 24.150 19.640 ;
      RECT 23.815 12.280 24.185 12.650 ;
      RECT 22.350 20.160 22.680 20.490 ;
      RECT 22.365 12.650 22.665 20.160 ;
      RECT 22.330 12.280 22.700 12.650 ;
      RECT 22.365 5.960 22.665 12.280 ;
      RECT 22.350 5.630 22.680 5.960 ;
      RECT 30.060 20.160 30.390 20.490 ;
      RECT 30.075 13.290 30.375 20.160 ;
      RECT 30.040 12.920 30.410 13.290 ;
      RECT 1.245 21.640 1.575 21.970 ;
      RECT 1.260 8.170 1.560 21.640 ;
      RECT 1.225 7.800 1.595 8.170 ;
      RECT 1.260 4.480 1.560 7.800 ;
      RECT 1.245 4.150 1.575 4.480 ;
      RECT 3.425 21.640 3.755 21.970 ;
      RECT 3.440 8.810 3.740 21.640 ;
      RECT 3.405 8.440 3.775 8.810 ;
      RECT 3.440 4.480 3.740 8.440 ;
      RECT 3.425 4.150 3.755 4.480 ;
      RECT 5.605 21.640 5.935 21.970 ;
      RECT 5.620 8.170 5.920 21.640 ;
      RECT 5.585 7.800 5.955 8.170 ;
      RECT 5.620 4.480 5.920 7.800 ;
      RECT 5.605 4.150 5.935 4.480 ;
      RECT 7.785 21.640 8.115 21.970 ;
      RECT 7.800 9.450 8.100 21.640 ;
      RECT 7.765 9.080 8.135 9.450 ;
      RECT 7.800 4.480 8.100 9.080 ;
      RECT 7.785 4.150 8.115 4.480 ;
      RECT 9.965 21.640 10.295 21.970 ;
      RECT 9.980 8.810 10.280 21.640 ;
      RECT 9.945 8.440 10.315 8.810 ;
      RECT 9.980 4.480 10.280 8.440 ;
      RECT 9.965 4.150 10.295 4.480 ;
      RECT 12.145 21.640 12.475 21.970 ;
      RECT 12.160 9.450 12.460 21.640 ;
      RECT 12.125 9.080 12.495 9.450 ;
      RECT 12.160 4.480 12.460 9.080 ;
      RECT 12.145 4.150 12.475 4.480 ;
      RECT 14.325 21.640 14.655 21.970 ;
      RECT 14.340 10.090 14.640 21.640 ;
      RECT 14.305 9.720 14.675 10.090 ;
      RECT 14.340 4.480 14.640 9.720 ;
      RECT 14.325 4.150 14.655 4.480 ;
      RECT 16.505 21.640 16.835 21.970 ;
      RECT 16.520 10.730 16.820 21.640 ;
      RECT 16.485 10.360 16.855 10.730 ;
      RECT 16.520 4.480 16.820 10.360 ;
      RECT 16.505 4.150 16.835 4.480 ;
      RECT 18.685 21.640 19.015 21.970 ;
      RECT 18.700 11.370 19.000 21.640 ;
      RECT 18.665 11.000 19.035 11.370 ;
      RECT 18.700 3.480 19.000 11.000 ;
      RECT 18.685 3.150 19.015 3.480 ;
      RECT 2.730 22.160 3.060 22.490 ;
      RECT 2.745 9.450 3.045 22.160 ;
      RECT 2.710 9.080 3.080 9.450 ;
      RECT 4.910 22.160 5.240 22.490 ;
      RECT 4.925 9.450 5.225 22.160 ;
      RECT 4.890 9.080 5.260 9.450 ;
      RECT 7.090 22.160 7.420 22.490 ;
      RECT 7.105 10.090 7.405 22.160 ;
      RECT 7.070 9.720 7.440 10.090 ;
      RECT 9.270 22.160 9.600 22.490 ;
      RECT 9.285 10.090 9.585 22.160 ;
      RECT 9.250 9.720 9.620 10.090 ;
      RECT 11.450 22.160 11.780 22.490 ;
      RECT 11.465 10.730 11.765 22.160 ;
      RECT 11.430 10.360 11.800 10.730 ;
      RECT 13.630 22.160 13.960 22.490 ;
      RECT 13.645 10.730 13.945 22.160 ;
      RECT 13.610 10.360 13.980 10.730 ;
      RECT 15.810 22.160 16.140 22.490 ;
      RECT 15.825 11.370 16.125 22.160 ;
      RECT 15.790 11.000 16.160 11.370 ;
      RECT 17.990 22.160 18.320 22.490 ;
      RECT 18.005 11.370 18.305 22.160 ;
      RECT 17.970 11.000 18.340 11.370 ;
      RECT 20.170 22.160 20.500 22.490 ;
      RECT 20.185 12.010 20.485 22.160 ;
      RECT 20.150 11.640 20.520 12.010 ;
      RECT 20.185 2.960 20.485 11.640 ;
      RECT 20.170 2.630 20.500 2.960 ;
      RECT 0.460 25.435 66.750 25.935 ;
      RECT 50.990 19.800 51.360 20.170 ;
      RECT 52.570 19.800 52.940 20.170 ;
      RECT 54.150 19.800 54.520 20.170 ;
      RECT 55.730 19.800 56.100 20.170 ;
      RECT 57.310 19.800 57.680 20.170 ;
      RECT 58.890 19.800 59.260 20.170 ;
      RECT 60.470 19.800 60.840 20.170 ;
      RECT 62.050 19.800 62.420 20.170 ;
      RECT 63.630 19.800 64.000 20.170 ;
      RECT 50.990 20.600 51.360 20.970 ;
      RECT 52.570 20.600 52.940 20.970 ;
      RECT 54.150 20.600 54.520 20.970 ;
      RECT 55.730 20.600 56.100 20.970 ;
      RECT 57.310 20.600 57.680 20.970 ;
      RECT 58.890 20.600 59.260 20.970 ;
      RECT 60.470 20.600 60.840 20.970 ;
      RECT 62.050 20.600 62.420 20.970 ;
      RECT 63.630 20.600 64.000 20.970 ;
      RECT 50.200 22.400 50.570 22.770 ;
      RECT 51.780 22.400 52.150 22.770 ;
      RECT 53.360 22.400 53.730 22.770 ;
      RECT 54.940 22.400 55.310 22.770 ;
      RECT 56.520 22.400 56.890 22.770 ;
      RECT 58.100 22.400 58.470 22.770 ;
      RECT 59.680 22.400 60.050 22.770 ;
      RECT 61.260 22.400 61.630 22.770 ;
      RECT 62.840 22.400 63.210 22.770 ;
      RECT 64.420 22.400 64.790 22.770 ;
      RECT 50.200 23.200 50.570 23.570 ;
      RECT 51.780 23.200 52.150 23.570 ;
      RECT 53.360 23.200 53.730 23.570 ;
      RECT 54.940 23.200 55.310 23.570 ;
      RECT 56.520 23.200 56.890 23.570 ;
      RECT 58.100 23.200 58.470 23.570 ;
      RECT 59.680 23.200 60.050 23.570 ;
      RECT 61.260 23.200 61.630 23.570 ;
      RECT 62.840 23.200 63.210 23.570 ;
      RECT 64.420 23.200 64.790 23.570 ;
      RECT 50.200 24.000 50.570 24.370 ;
      RECT 51.780 24.000 52.150 24.370 ;
      RECT 53.360 24.000 53.730 24.370 ;
      RECT 54.940 24.000 55.310 24.370 ;
      RECT 56.520 24.000 56.890 24.370 ;
      RECT 58.100 24.000 58.470 24.370 ;
      RECT 59.680 24.000 60.050 24.370 ;
      RECT 61.260 24.000 61.630 24.370 ;
      RECT 62.840 24.000 63.210 24.370 ;
      RECT 64.420 24.000 64.790 24.370 ;
      RECT 47.040 22.400 47.410 22.770 ;
      RECT 48.620 22.400 48.990 22.770 ;
      RECT 44.670 19.800 45.040 20.170 ;
      RECT 46.250 19.800 46.620 20.170 ;
      RECT 33.610 20.600 33.980 20.970 ;
      RECT 35.190 20.600 35.560 20.970 ;
      RECT 36.770 20.600 37.140 20.970 ;
      RECT 38.350 20.600 38.720 20.970 ;
      RECT 39.930 20.600 40.300 20.970 ;
      RECT 41.510 20.600 41.880 20.970 ;
      RECT 43.090 20.600 43.460 20.970 ;
      RECT 44.670 20.600 45.040 20.970 ;
      RECT 34.400 23.200 34.770 23.570 ;
      RECT 35.980 23.200 36.350 23.570 ;
      RECT 37.560 23.200 37.930 23.570 ;
      RECT 39.140 23.200 39.510 23.570 ;
      RECT 40.720 23.200 41.090 23.570 ;
      RECT 42.300 23.200 42.670 23.570 ;
      RECT 43.880 23.200 44.250 23.570 ;
      RECT 45.460 23.200 45.830 23.570 ;
      RECT 47.040 23.200 47.410 23.570 ;
      RECT 48.620 23.200 48.990 23.570 ;
      RECT 46.250 20.600 46.620 20.970 ;
      RECT 47.830 20.600 48.200 20.970 ;
      RECT 49.410 20.600 49.780 20.970 ;
      RECT 47.830 19.800 48.200 20.170 ;
      RECT 49.410 19.800 49.780 20.170 ;
      RECT 33.610 19.800 33.980 20.170 ;
      RECT 35.190 19.800 35.560 20.170 ;
      RECT 36.770 19.800 37.140 20.170 ;
      RECT 38.350 19.800 38.720 20.170 ;
      RECT 39.930 19.800 40.300 20.170 ;
      RECT 34.400 24.000 34.770 24.370 ;
      RECT 35.980 24.000 36.350 24.370 ;
      RECT 37.560 24.000 37.930 24.370 ;
      RECT 39.140 24.000 39.510 24.370 ;
      RECT 40.720 24.000 41.090 24.370 ;
      RECT 42.300 24.000 42.670 24.370 ;
      RECT 43.880 24.000 44.250 24.370 ;
      RECT 45.460 24.000 45.830 24.370 ;
      RECT 47.040 24.000 47.410 24.370 ;
      RECT 48.620 24.000 48.990 24.370 ;
      RECT 41.510 19.800 41.880 20.170 ;
      RECT 43.090 19.800 43.460 20.170 ;
      RECT 34.400 22.400 34.770 22.770 ;
      RECT 35.980 22.400 36.350 22.770 ;
      RECT 37.560 22.400 37.930 22.770 ;
      RECT 39.140 22.400 39.510 22.770 ;
      RECT 40.720 22.400 41.090 22.770 ;
      RECT 42.300 22.400 42.670 22.770 ;
      RECT 43.880 22.400 44.250 22.770 ;
      RECT 45.460 22.400 45.830 22.770 ;
      RECT 46.250 15.000 46.620 15.370 ;
      RECT 47.830 15.000 48.200 15.370 ;
      RECT 49.410 15.000 49.780 15.370 ;
      RECT 33.610 15.800 33.980 16.170 ;
      RECT 35.190 15.800 35.560 16.170 ;
      RECT 49.410 18.200 49.780 18.570 ;
      RECT 33.610 19.000 33.980 19.370 ;
      RECT 35.190 19.000 35.560 19.370 ;
      RECT 36.770 19.000 37.140 19.370 ;
      RECT 38.350 19.000 38.720 19.370 ;
      RECT 39.930 19.000 40.300 19.370 ;
      RECT 41.510 19.000 41.880 19.370 ;
      RECT 43.090 19.000 43.460 19.370 ;
      RECT 44.670 19.000 45.040 19.370 ;
      RECT 46.250 19.000 46.620 19.370 ;
      RECT 47.830 19.000 48.200 19.370 ;
      RECT 49.410 19.000 49.780 19.370 ;
      RECT 33.610 15.000 33.980 15.370 ;
      RECT 35.190 15.000 35.560 15.370 ;
      RECT 38.350 15.800 38.720 16.170 ;
      RECT 39.930 15.800 40.300 16.170 ;
      RECT 41.510 15.800 41.880 16.170 ;
      RECT 43.090 15.800 43.460 16.170 ;
      RECT 44.670 15.800 45.040 16.170 ;
      RECT 46.250 15.800 46.620 16.170 ;
      RECT 47.830 15.800 48.200 16.170 ;
      RECT 49.410 15.800 49.780 16.170 ;
      RECT 33.610 16.600 33.980 16.970 ;
      RECT 35.190 16.600 35.560 16.970 ;
      RECT 36.770 16.600 37.140 16.970 ;
      RECT 38.350 16.600 38.720 16.970 ;
      RECT 39.930 16.600 40.300 16.970 ;
      RECT 41.510 16.600 41.880 16.970 ;
      RECT 43.090 16.600 43.460 16.970 ;
      RECT 44.670 16.600 45.040 16.970 ;
      RECT 46.250 16.600 46.620 16.970 ;
      RECT 47.830 16.600 48.200 16.970 ;
      RECT 49.410 16.600 49.780 16.970 ;
      RECT 33.610 17.400 33.980 17.770 ;
      RECT 36.770 15.000 37.140 15.370 ;
      RECT 38.350 15.000 38.720 15.370 ;
      RECT 35.190 17.400 35.560 17.770 ;
      RECT 36.770 17.400 37.140 17.770 ;
      RECT 38.350 17.400 38.720 17.770 ;
      RECT 39.930 17.400 40.300 17.770 ;
      RECT 41.510 17.400 41.880 17.770 ;
      RECT 43.090 17.400 43.460 17.770 ;
      RECT 44.670 17.400 45.040 17.770 ;
      RECT 46.250 17.400 46.620 17.770 ;
      RECT 47.830 17.400 48.200 17.770 ;
      RECT 49.410 17.400 49.780 17.770 ;
      RECT 33.610 18.200 33.980 18.570 ;
      RECT 35.190 18.200 35.560 18.570 ;
      RECT 36.770 18.200 37.140 18.570 ;
      RECT 38.350 18.200 38.720 18.570 ;
      RECT 39.930 18.200 40.300 18.570 ;
      RECT 41.510 18.200 41.880 18.570 ;
      RECT 43.090 18.200 43.460 18.570 ;
      RECT 44.670 18.200 45.040 18.570 ;
      RECT 46.250 18.200 46.620 18.570 ;
      RECT 47.830 18.200 48.200 18.570 ;
      RECT 39.930 15.000 40.300 15.370 ;
      RECT 41.510 15.000 41.880 15.370 ;
      RECT 43.090 15.000 43.460 15.370 ;
      RECT 44.670 15.000 45.040 15.370 ;
      RECT 36.770 15.800 37.140 16.170 ;
      RECT 58.890 15.800 59.260 16.170 ;
      RECT 50.990 18.200 51.360 18.570 ;
      RECT 52.570 18.200 52.940 18.570 ;
      RECT 54.150 18.200 54.520 18.570 ;
      RECT 55.730 18.200 56.100 18.570 ;
      RECT 57.310 18.200 57.680 18.570 ;
      RECT 58.890 18.200 59.260 18.570 ;
      RECT 60.470 18.200 60.840 18.570 ;
      RECT 62.050 18.200 62.420 18.570 ;
      RECT 63.630 18.200 64.000 18.570 ;
      RECT 60.470 15.800 60.840 16.170 ;
      RECT 62.050 15.800 62.420 16.170 ;
      RECT 63.630 15.800 64.000 16.170 ;
      RECT 50.990 15.800 51.360 16.170 ;
      RECT 52.570 15.800 52.940 16.170 ;
      RECT 50.990 16.600 51.360 16.970 ;
      RECT 52.570 16.600 52.940 16.970 ;
      RECT 50.990 17.400 51.360 17.770 ;
      RECT 52.570 17.400 52.940 17.770 ;
      RECT 54.150 17.400 54.520 17.770 ;
      RECT 55.730 17.400 56.100 17.770 ;
      RECT 50.990 19.000 51.360 19.370 ;
      RECT 52.570 19.000 52.940 19.370 ;
      RECT 54.150 19.000 54.520 19.370 ;
      RECT 55.730 19.000 56.100 19.370 ;
      RECT 57.310 19.000 57.680 19.370 ;
      RECT 58.890 19.000 59.260 19.370 ;
      RECT 60.470 19.000 60.840 19.370 ;
      RECT 62.050 19.000 62.420 19.370 ;
      RECT 63.630 19.000 64.000 19.370 ;
      RECT 57.310 17.400 57.680 17.770 ;
      RECT 58.890 17.400 59.260 17.770 ;
      RECT 60.470 17.400 60.840 17.770 ;
      RECT 62.050 17.400 62.420 17.770 ;
      RECT 63.630 17.400 64.000 17.770 ;
      RECT 54.150 16.600 54.520 16.970 ;
      RECT 50.990 15.000 51.360 15.370 ;
      RECT 52.570 15.000 52.940 15.370 ;
      RECT 54.150 15.000 54.520 15.370 ;
      RECT 55.730 15.000 56.100 15.370 ;
      RECT 57.310 15.000 57.680 15.370 ;
      RECT 58.890 15.000 59.260 15.370 ;
      RECT 60.470 15.000 60.840 15.370 ;
      RECT 62.050 15.000 62.420 15.370 ;
      RECT 63.630 15.000 64.000 15.370 ;
      RECT 55.730 16.600 56.100 16.970 ;
      RECT 57.310 16.600 57.680 16.970 ;
      RECT 58.890 16.600 59.260 16.970 ;
      RECT 60.470 16.600 60.840 16.970 ;
      RECT 62.050 16.600 62.420 16.970 ;
      RECT 63.630 16.600 64.000 16.970 ;
      RECT 54.150 15.800 54.520 16.170 ;
      RECT 55.730 15.800 56.100 16.170 ;
      RECT 57.310 15.800 57.680 16.170 ;
      RECT 32.820 22.400 33.190 22.770 ;
      RECT 32.820 23.200 33.190 23.570 ;
      RECT 32.820 24.000 33.190 24.370 ;
      RECT 6.280 9.720 6.650 10.090 ;
      RECT 6.315 1.260 6.615 9.720 ;
      RECT 6.300 0.930 6.630 1.260 ;
      RECT 10.640 10.360 11.010 10.730 ;
      RECT 10.675 1.260 10.975 10.360 ;
      RECT 10.660 0.930 10.990 1.260 ;
      RECT 15.000 11.000 15.370 11.370 ;
      RECT 15.035 1.260 15.335 11.000 ;
      RECT 15.020 0.930 15.350 1.260 ;
      RECT 23.025 12.280 23.395 12.650 ;
      RECT 23.060 6.480 23.360 12.280 ;
      RECT 23.045 6.150 23.375 6.480 ;
      RECT 32.820 1.600 33.190 1.970 ;
      RECT 32.820 2.400 33.190 2.770 ;
      RECT 1.920 9.080 2.290 9.450 ;
      RECT 1.955 1.260 2.255 9.080 ;
      RECT 1.940 0.930 2.270 1.260 ;
      RECT 54.150 4.000 54.520 4.370 ;
      RECT 55.730 4.000 56.100 4.370 ;
      RECT 57.310 4.000 57.680 4.370 ;
      RECT 58.890 4.000 59.260 4.370 ;
      RECT 60.470 4.000 60.840 4.370 ;
      RECT 62.050 4.000 62.420 4.370 ;
      RECT 63.630 4.000 64.000 4.370 ;
      RECT 33.610 4.800 33.980 5.170 ;
      RECT 35.190 4.800 35.560 5.170 ;
      RECT 36.770 4.800 37.140 5.170 ;
      RECT 38.350 4.800 38.720 5.170 ;
      RECT 39.930 4.800 40.300 5.170 ;
      RECT 41.510 4.800 41.880 5.170 ;
      RECT 43.090 4.800 43.460 5.170 ;
      RECT 44.670 4.800 45.040 5.170 ;
      RECT 46.250 4.800 46.620 5.170 ;
      RECT 47.830 4.800 48.200 5.170 ;
      RECT 49.410 4.800 49.780 5.170 ;
      RECT 50.990 4.800 51.360 5.170 ;
      RECT 52.570 4.800 52.940 5.170 ;
      RECT 54.150 4.800 54.520 5.170 ;
      RECT 55.730 4.800 56.100 5.170 ;
      RECT 57.310 4.800 57.680 5.170 ;
      RECT 58.890 4.800 59.260 5.170 ;
      RECT 60.470 4.800 60.840 5.170 ;
      RECT 62.050 4.800 62.420 5.170 ;
      RECT 63.630 4.800 64.000 5.170 ;
      RECT 33.610 5.600 33.980 5.970 ;
      RECT 35.190 5.600 35.560 5.970 ;
      RECT 36.770 5.600 37.140 5.970 ;
      RECT 38.350 5.600 38.720 5.970 ;
      RECT 39.930 5.600 40.300 5.970 ;
      RECT 41.510 5.600 41.880 5.970 ;
      RECT 43.090 5.600 43.460 5.970 ;
      RECT 44.670 5.600 45.040 5.970 ;
      RECT 46.250 5.600 46.620 5.970 ;
      RECT 47.830 5.600 48.200 5.970 ;
      RECT 49.410 5.600 49.780 5.970 ;
      RECT 50.990 5.600 51.360 5.970 ;
      RECT 52.570 5.600 52.940 5.970 ;
      RECT 54.150 5.600 54.520 5.970 ;
      RECT 55.730 5.600 56.100 5.970 ;
      RECT 57.310 5.600 57.680 5.970 ;
      RECT 58.890 5.600 59.260 5.970 ;
      RECT 60.470 5.600 60.840 5.970 ;
      RECT 62.050 5.600 62.420 5.970 ;
      RECT 63.630 5.600 64.000 5.970 ;
      RECT 35.980 1.600 36.350 1.970 ;
      RECT 37.560 1.600 37.930 1.970 ;
      RECT 39.140 1.600 39.510 1.970 ;
      RECT 40.720 1.600 41.090 1.970 ;
      RECT 42.300 1.600 42.670 1.970 ;
      RECT 43.880 1.600 44.250 1.970 ;
      RECT 45.460 1.600 45.830 1.970 ;
      RECT 47.040 1.600 47.410 1.970 ;
      RECT 48.620 1.600 48.990 1.970 ;
      RECT 50.200 1.600 50.570 1.970 ;
      RECT 51.780 1.600 52.150 1.970 ;
      RECT 53.360 1.600 53.730 1.970 ;
      RECT 54.940 1.600 55.310 1.970 ;
      RECT 56.520 1.600 56.890 1.970 ;
      RECT 58.100 1.600 58.470 1.970 ;
      RECT 59.680 1.600 60.050 1.970 ;
      RECT 61.260 1.600 61.630 1.970 ;
      RECT 62.840 1.600 63.210 1.970 ;
      RECT 64.420 1.600 64.790 1.970 ;
      RECT 34.400 1.600 34.770 1.970 ;
      RECT 34.400 2.400 34.770 2.770 ;
      RECT 35.980 2.400 36.350 2.770 ;
      RECT 37.560 2.400 37.930 2.770 ;
      RECT 39.140 2.400 39.510 2.770 ;
      RECT 40.720 2.400 41.090 2.770 ;
      RECT 42.300 2.400 42.670 2.770 ;
      RECT 43.880 2.400 44.250 2.770 ;
      RECT 45.460 2.400 45.830 2.770 ;
      RECT 47.040 2.400 47.410 2.770 ;
      RECT 48.620 2.400 48.990 2.770 ;
      RECT 50.200 2.400 50.570 2.770 ;
      RECT 51.780 2.400 52.150 2.770 ;
      RECT 53.360 2.400 53.730 2.770 ;
      RECT 54.940 2.400 55.310 2.770 ;
      RECT 56.520 2.400 56.890 2.770 ;
      RECT 58.100 2.400 58.470 2.770 ;
      RECT 59.680 2.400 60.050 2.770 ;
      RECT 61.260 2.400 61.630 2.770 ;
      RECT 62.840 2.400 63.210 2.770 ;
      RECT 64.420 2.400 64.790 2.770 ;
      RECT 33.610 4.000 33.980 4.370 ;
      RECT 35.190 4.000 35.560 4.370 ;
      RECT 36.770 4.000 37.140 4.370 ;
      RECT 38.350 4.000 38.720 4.370 ;
      RECT 39.930 4.000 40.300 4.370 ;
      RECT 41.510 4.000 41.880 4.370 ;
      RECT 43.090 4.000 43.460 4.370 ;
      RECT 44.670 4.000 45.040 4.370 ;
      RECT 46.250 4.000 46.620 4.370 ;
      RECT 47.830 4.000 48.200 4.370 ;
      RECT 49.410 4.000 49.780 4.370 ;
      RECT 50.990 4.000 51.360 4.370 ;
      RECT 52.570 4.000 52.940 4.370 ;
    LAYER met3 ;
      RECT 32.660 0.985 65.510 3.085 ;
      RECT 1.700 8.455 10.380 8.795 ;
      RECT 1.855 9.095 12.560 9.435 ;
      RECT 6.215 9.735 14.740 10.075 ;
      RECT 10.575 10.375 16.920 10.715 ;
      RECT 14.935 11.015 19.100 11.355 ;
      RECT 20.085 11.655 21.280 11.995 ;
      RECT 22.265 12.295 24.250 12.635 ;
      RECT 26.025 12.935 32.560 13.275 ;
      RECT 33.460 3.535 65.510 21.685 ;
      RECT 32.660 22.135 65.510 24.985 ;
  END
END wbuf

END LIBRARY
